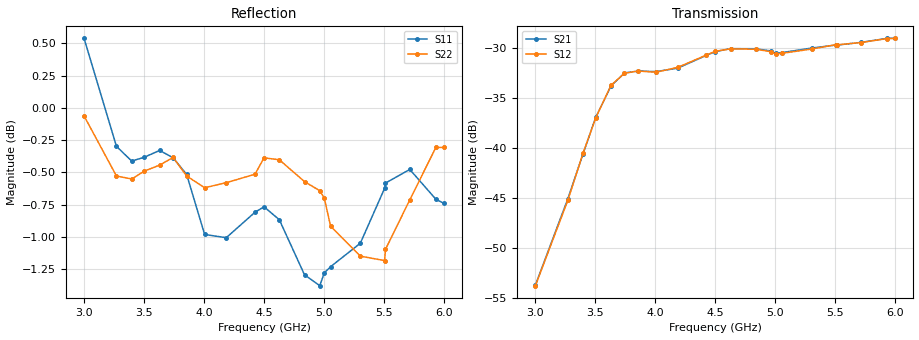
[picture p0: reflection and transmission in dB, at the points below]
!  26/11/2025  17:25:32
! Ref Plane: 0.000 mm
# MHZ S MA R  50
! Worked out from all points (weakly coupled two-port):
!   401 points, 3 GHz to 6 GHz, reference 50 ohm
!   highest |S21| = -29.06 dB at 5.933 GHz (marker M1); lowest = -53.7 dB at 3 GHz (marker M2)
!   lowest |S11| = -1.4 dB at 4.965 GHz (marker M3), VSWR 12.64, Z = 8.67 - j54.2 ohm
!   |S11| at or under -10 dB: nowhere
!   |S22| runs from -1.2 to 0.0 dB; largest |S21 - S12| = 0.0014
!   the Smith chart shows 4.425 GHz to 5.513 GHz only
!   S11 on the Smith chart (normalised r, x): 4.425 GHz: 0.10, +1.03; 4.628 GHz: 1.28, +4.81; 4.838 GHz: 0.49, -2.31; 5.055 GHz: 0.10, -0.69; 5.303 GHz: 0.06, -0.01; 5.513 GHz: 0.05, +0.59
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3000  1.064 -136.8  0.002054 46.6  0.002039 50.7  0.9929 -105.6
3270  0.9663 152.6  0.005546 -18.5  0.005447 -14.5  0.9411 -170.2
3397.5  0.9537 109.1  0.00934 -58.2  0.009399 -57.5  0.9386 151.0
3502.5  0.957 66.1  0.01416 -98.9  0.01409 -97.9  0.9452 113.2
3630  0.9628 11.0  0.02038 -154.9  0.02052 -153.6  0.9503 58.5
3742.5  0.9565 -38.7  0.02365 155.2  0.02356 156.7  0.9568 10.5
3855  0.9424 -84.1  0.02418 109.2  0.0242 110.5  0.9411 -35.4
4005  0.8933 -137.8  0.02403 56.5  0.02385 57.5  0.9313 -87.5
4185  0.8907 165.2  0.02499 1.7  0.02522 3.5  0.9355 -144.1
4425  0.9112 87.9  0.02897 -72.4  0.02908 -71.0  0.9426 142.4
4500  0.9156 63.4  0.03026 -97.1  0.03038 -95.7  0.9565 119.5
4627.5  0.9051 22.0  0.03132 -138.2  0.03124 -137.2  0.9548 80.2
4837.5  0.8617 -45.2  0.03127 155.2  0.03108 156.9  0.9364 16.5
4965  0.8534 -84.5  0.03047 118.7  0.03021 120.1  0.9288 -19.7
5002.5  0.8632 -95.9  0.02963 108.4  0.02937 109.5  0.9227 -31.5
5055  0.868 -110.7  0.02992 93.6  0.02966 94.3  0.8999 -47.3
5302.5  0.8863 -178.6  0.03151 25.4  0.03116 26.6  0.8762 -118.1
5505  0.9308 120.4  0.03263 -31.5  0.03277 -29.6  0.8727 -173.0
5512.5  0.9352 119.1  0.03261 -33.3  0.0327 -31.4  0.8815 -175.9
5715  0.9466 61.3  0.03365 -91.5  0.03359 -89.3  0.9213 127.3
5932.5  0.9218 -1.5  0.03524 -153.6  0.03518 -152.0  0.9654 70.7
6000  0.9184 -21.4  0.03524 -172.9  0.03519 -171.5  0.9654 53.6
